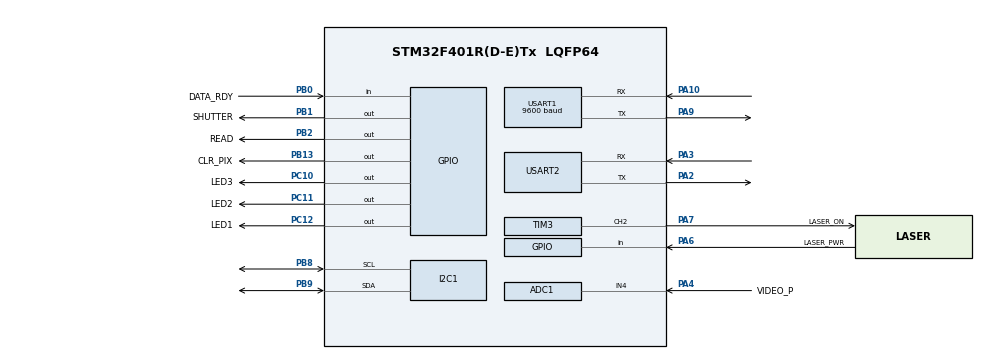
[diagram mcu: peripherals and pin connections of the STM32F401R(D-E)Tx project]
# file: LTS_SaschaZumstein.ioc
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ADC1.Channel-0\#ChannelRegularConversion=ADC_CHANNEL_4
ADC1.NbrOfConversionFlag=1
ADC1.Rank-0\#ChannelRegularConversion=1
ADC1.SamplingTime-0\#ChannelRegularConversion=ADC_SAMPLETIME_3CYCLES
ADC1.master=1
I2C1.I2C_Mode=I2C_Fast
Mcu.Family=STM32F4
Mcu.Name=STM32F401R(D-E)Tx
Mcu.Package=LQFP64
NVIC.PriorityGroup=NVIC_PRIORITYGROUP_4
PA10.Mode=Asynchronous
PA10.Signal=USART1_RX
PA13.Signal=SYS_JTMS-SWDIO
PA14.Signal=SYS_JTCK-SWCLK
PA2.Mode=Asynchronous
PA2.Signal=USART2_TX
PA3.Mode=Asynchronous
PA3.Signal=USART2_RX
PA4.GPIO_Label=VIDEO_P
PA4.Signal=SharedAnalog_PA4
PA6.GPIO_Label=LASER_PWR
PA6.Signal=GPIO_Input
PA7.GPIO_Label=LASER_ON
PA7.Signal=S_TIM3_CH2
PA9.Mode=Asynchronous
PA9.Signal=USART1_TX
PB0.GPIO_Label=DATA_RDY
PB0.Signal=GPIO_Input
PB1.GPIO_Label=SHUTTER
PB1.Signal=GPIO_Output
PB13.GPIO_Label=CLR_PIX
PB13.Signal=GPIO_Output
PB2.GPIO_Label=READ
PB2.Signal=GPIO_Output
PB8.Mode=I2C
PB8.Signal=I2C1_SCL
PB9.Mode=I2C
PB9.Signal=I2C1_SDA
PC10.GPIO_Label=LED3
PC10.Signal=GPIO_Output
PC11.GPIO_Label=LED2
PC11.Signal=GPIO_Output
PC12.GPIO_Label=LED1
PC12.Signal=GPIO_Output
ProjectManager.HeapSize=0x200
ProjectManager.StackSize=0x400
ProjectManager.TargetToolchain=STM32CubeIDE
RCC.AHBFreq_Value=16000000
RCC.APB1Freq_Value=16000000
RCC.APB2Freq_Value=16000000
RCC.CortexFreq_Value=16000000
RCC.HSE_VALUE=25000000
RCC.HSI_VALUE=16000000
RCC.LSE_VALUE=32768
RCC.SYSCLKFreq_VALUE=16000000
RCC.VCOOutputFreq_Value=192000000
SH.S_TIM3_CH2.0=TIM3_CH2,PWM Generation2 CH2
SH.SharedAnalog_PA4.0=GPIO_Analog
SH.SharedAnalog_PA4.1=ADC1_IN4,IN4
TIM3.Channel-PWM\ Generation2\ CH2=TIM_CHANNEL_2
TIM3.Period=49
TIM3.Prescaler=16-1
TIM3.Pulse-PWM\ Generation2\ CH2=15
TIM9.Prescaler=16-1
USART1.BaudRate=9600
USART1.VirtualMode=VM_ASYNC
USART2.VirtualMode=VM_ASYNC
VP_TIM3_VS_ClockSourceINT.Mode=Internal
VP_TIM9_VS_ClockSourceINT.Mode=Internal
board=custom

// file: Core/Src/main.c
/* USER CODE BEGIN Header */
/**
 ******************************************************************************
 * @file           : main.c
 * @brief          : Main program body
 ******************************************************************************
 * @attention
 *
 * Copyright (c) 2024 STMicroelectronics.
 * All rights reserved.
 *
 * This software is licensed under terms that can be found in the LICENSE file
 * in the root directory of this software component.
 * If no LICENSE file comes with this software, it is provided AS-IS.
 *
 ******************************************************************************
 */
/* USER CODE END Header */
#include "main.h"

/* USER CODE BEGIN Includes */
#include <stdio.h>
#include <stdbool.h>
#include "ssd1306.h"
#include "epc901.h"
#include "logic.h"

/* USER CODE END Includes */

/* USER CODE BEGIN PD */
#define NUM_OF_PIX 		1024
#define LASER_ON 		HAL_TIM_PWM_Start(&htim3, TIM_CHANNEL_2);
#define LASER_OFF		HAL_TIM_PWM_Stop(&htim3, TIM_CHANNEL_2);
#define LED_PWR_ON		HAL_GPIO_WritePin(LED1_GPIO_Port, LED1_Pin, GPIO_PIN_SET);
#define LED_PWR_OFF		HAL_GPIO_WritePin(LED1_GPIO_Port, LED1_Pin, GPIO_PIN_RESET);
#define LED_MEASURE_ON	HAL_GPIO_WritePin(LED2_GPIO_Port, LED2_Pin, GPIO_PIN_SET);
#define LED_MEASURE_OFF	HAL_GPIO_WritePin(LED2_GPIO_Port, LED2_Pin, GPIO_PIN_RESET);
#define LED_ERROR_ON	HAL_GPIO_WritePin(LED3_GPIO_Port, LED3_Pin, GPIO_PIN_SET);
#define LED_ERROR_OFF	HAL_GPIO_WritePin(LED3_GPIO_Port, LED3_Pin, GPIO_PIN_RESET);
#define CHECK_STATUS(status)       \
	do {                    	\
	if ((status) != HAL_OK) {	\
		Error_Handler();     	\
	}                        	\
} while (0)
/* USER CODE END PD */

ADC_HandleTypeDef hadc1;

I2C_HandleTypeDef hi2c1;

IWDG_HandleTypeDef hiwdg;

TIM_HandleTypeDef htim3;
TIM_HandleTypeDef htim9;

UART_HandleTypeDef huart1;
UART_HandleTypeDef huart2;

/* USER CODE BEGIN PV */
uint8_t rxBuffer[1];
volatile bool debugMode = false;
volatile bool fastMode = false;
/* USER CODE END PV */

void SystemClock_Config(void);
static void MX_GPIO_Init(void);
static void MX_ADC1_Init(void);
static void MX_I2C1_Init(void);
static void MX_USART1_UART_Init(void);
static void MX_USART2_UART_Init(void);
static void MX_TIM9_Init(void);
static void MX_TIM3_Init(void);
static void MX_IWDG_Init(void);

int main(void) {

	/* USER CODE BEGIN 1 */
	uint16_t distance = UINT16_MAX;
	char distStr[9];
	uint16_t shutterTime = 125;
	char shutterStr[22];
	uint16_t measureData[NUM_OF_PIX] = { 0 };
	uint16_t minVal = UINT16_MAX;
	uint16_t maxVal = 0;
	uint16_t maxIndex = 0;
	uint8_t txBuffer[1];
	/* USER CODE END 1 */

	/* MCU Configuration--------------------------------------------------------*/

	/* Reset of all peripherals, Initializes the Flash interface and the Systick. */
	HAL_Init();

	/* Configure the system clock */
	SystemClock_Config();

	/* USER CODE BEGIN SysInit */
	HAL_Delay(200); // delay to ensure that the display startup works correctly
	/* USER CODE END SysInit */

	/* Initialize all configured peripherals */
	MX_GPIO_Init();
	MX_ADC1_Init();
	MX_I2C1_Init();
	MX_USART1_UART_Init();
	MX_USART2_UART_Init();
	MX_TIM9_Init();
	MX_TIM3_Init();
	MX_IWDG_Init();
	/* USER CODE BEGIN 2 */
	// init display
	CHECK_STATUS(SSD1306_Init());
	SSD1306_PrintData("LTS Startup", "Please Wait");
	// init epc901
	CHECK_STATUS(HAL_TIM_Base_Start(&htim9));
	CHECK_STATUS(epc901_init());
	// init UART
	CHECK_STATUS(HAL_UART_Receive_IT(&huart2, rxBuffer, 1));
	logic_writeData("\r\n\n-- LTS Startup Please Wait --\r\n", 34, false);
	// delay to display startup screen
	for (int i = 0; i < 10; i++) {
		HAL_IWDG_Refresh(&hiwdg);
		HAL_Delay(200);
	}
	// startup sucessfully
	LASER_ON
	LED_PWR_ON
	LED_ERROR_OFF
	LED_MEASURE_OFF
	logic_writeData("\r\n\n-- LTS Startup successfully --\r\n", 35, false);
	SSD1306_Clear();
	/* USER CODE END 2 */

	/* Infinite loop */
	/* USER CODE BEGIN WHILE */
	while (1) {
		// get the data from the epc901
		CHECK_STATUS(epc901_getData(shutterTime, measureData, &minVal, &maxVal, &maxIndex));
		// regulate shutter time
		logic_adjustShutterTime(&shutterTime, minVal, maxVal);
		// calculate distance and make an average over the last values
		distance = logic_movingAverage(logic_calcDist(measureData, minVal, maxVal, maxIndex));

		if (distance == UINT16_MAX) { // measurement not successful
			if (!fastMode){ // don't write to the display in fast mode
				CHECK_STATUS(SSD1306_PrintData("Distance:", "---- mm"));
			}
			logic_writeData("Distance: ---- mm\r\n", 19, fastMode);
			LED_MEASURE_OFF
		}
		else { // measurement successful
			sprintf(distStr, "%4d mm", distance);
			if (!fastMode){ // don't write to the display in fast mode
				CHECK_STATUS(SSD1306_PrintData("Distance:", distStr));
			}
			logic_writeData("Distance: ", 10, fastMode);
			logic_writeData(distStr, 7, fastMode);
			logic_writeData("\r\n", 2, fastMode);
			LED_MEASURE_ON
		}

		// send shutter time and measured data via serial only if debug mode is activated
		if (debugMode) {
			sprintf(shutterStr, "Shutter Time: %4d\r\n", shutterTime);
			logic_writeData(shutterStr, 20, false);

			// transmit the data
			logic_writeData("START DATA\r\n", 12, true);
			for (int i = 0; i < NUM_OF_PIX; i++) {
				txBuffer[0] = measureData[i] >> 4;
				HAL_UART_Transmit(&huart2, txBuffer, 1, HAL_MAX_DELAY);
			}
			logic_writeData("\r\nEND DATA\r\n", 12, true);
		}
		/* USER CODE END WHILE */

		/* USER CODE BEGIN 3 */
		HAL_IWDG_Refresh(&hiwdg); // refresh watchdog
	}
	return 0;
	/* USER CODE END 3 */
}

void SystemClock_Config(void) {
	RCC_OscInitTypeDef RCC_OscInitStruct = { 0 };
	RCC_ClkInitTypeDef RCC_ClkInitStruct = { 0 };

	/** Configure the main internal regulator output voltage
	 */
	__HAL_RCC_PWR_CLK_ENABLE();
	__HAL_PWR_VOLTAGESCALING_CONFIG(PWR_REGULATOR_VOLTAGE_SCALE2);

	/** Initializes the RCC Oscillators according to the specified parameters
	 * in the RCC_OscInitTypeDef structure.
	 */
	RCC_OscInitStruct.OscillatorType = RCC_OSCILLATORTYPE_HSI
			| RCC_OSCILLATORTYPE_LSI;
	RCC_OscInitStruct.HSIState = RCC_HSI_ON;
	RCC_OscInitStruct.HSICalibrationValue = RCC_HSICALIBRATION_DEFAULT;
	RCC_OscInitStruct.LSIState = RCC_LSI_ON;
	RCC_OscInitStruct.PLL.PLLState = RCC_PLL_ON;
	RCC_OscInitStruct.PLL.PLLSource = RCC_PLLSOURCE_HSI;
	RCC_OscInitStruct.PLL.PLLM = 8;
	RCC_OscInitStruct.PLL.PLLN = 84;
	RCC_OscInitStruct.PLL.PLLP = RCC_PLLP_DIV2;
	RCC_OscInitStruct.PLL.PLLQ = 4;
	if (HAL_RCC_OscConfig(&RCC_OscInitStruct) != HAL_OK) {
		Error_Handler();
	}

	/** Initializes the CPU, AHB and APB buses clocks
	 */
	RCC_ClkInitStruct.ClockType = RCC_CLOCKTYPE_HCLK | RCC_CLOCKTYPE_SYSCLK
			| RCC_CLOCKTYPE_PCLK1 | RCC_CLOCKTYPE_PCLK2;
	RCC_ClkInitStruct.SYSCLKSource = RCC_SYSCLKSOURCE_PLLCLK;
	RCC_ClkInitStruct.AHBCLKDivider = RCC_SYSCLK_DIV1;
	RCC_ClkInitStruct.APB1CLKDivider = RCC_HCLK_DIV2;
	RCC_ClkInitStruct.APB2CLKDivider = RCC_HCLK_DIV1;

	if (HAL_RCC_ClockConfig(&RCC_ClkInitStruct, FLASH_LATENCY_2) != HAL_OK) {
		Error_Handler();
	}
}

static void MX_ADC1_Init(void) {

	ADC_ChannelConfTypeDef sConfig = { 0 };

	/** Configure the global features of the ADC (Clock, Resolution, Data Alignment and number of conversion)
	 */
	hadc1.Instance = ADC1;
	hadc1.Init.ClockPrescaler = ADC_CLOCK_SYNC_PCLK_DIV4;
	hadc1.Init.Resolution = ADC_RESOLUTION_12B;
	hadc1.Init.ScanConvMode = DISABLE;
	hadc1.Init.ContinuousConvMode = DISABLE;
	hadc1.Init.DiscontinuousConvMode = DISABLE;
	hadc1.Init.ExternalTrigConvEdge = ADC_EXTERNALTRIGCONVEDGE_NONE;
	hadc1.Init.ExternalTrigConv = ADC_SOFTWARE_START;
	hadc1.Init.DataAlign = ADC_DATAALIGN_RIGHT;
	hadc1.Init.NbrOfConversion = 1;
	hadc1.Init.DMAContinuousRequests = DISABLE;
	hadc1.Init.EOCSelection = ADC_EOC_SINGLE_CONV;
	if (HAL_ADC_Init(&hadc1) != HAL_OK) {
		Error_Handler();
	}

	/** Configure for the selected ADC regular channel its corresponding rank in the sequencer and its sample time.
	 */
	sConfig.Channel = ADC_CHANNEL_4;
	sConfig.Rank = 1;
	sConfig.SamplingTime = ADC_SAMPLETIME_3CYCLES;
	if (HAL_ADC_ConfigChannel(&hadc1, &sConfig) != HAL_OK) {
		Error_Handler();
	}

}

static void MX_I2C1_Init(void) {

	hi2c1.Instance = I2C1;
	hi2c1.Init.ClockSpeed = 400000;
	hi2c1.Init.DutyCycle = I2C_DUTYCYCLE_2;
	hi2c1.Init.OwnAddress1 = 0;
	hi2c1.Init.AddressingMode = I2C_ADDRESSINGMODE_7BIT;
	hi2c1.Init.DualAddressMode = I2C_DUALADDRESS_DISABLE;
	hi2c1.Init.OwnAddress2 = 0;
	hi2c1.Init.GeneralCallMode = I2C_GENERALCALL_DISABLE;
	hi2c1.Init.NoStretchMode = I2C_NOSTRETCH_DISABLE;
	if (HAL_I2C_Init(&hi2c1) != HAL_OK) {
		Error_Handler();
	}

}

static void MX_IWDG_Init(void) {

	hiwdg.Instance = IWDG;
	hiwdg.Init.Prescaler = IWDG_PRESCALER_8;
	hiwdg.Init.Reload = 4095;
	if (HAL_IWDG_Init(&hiwdg) != HAL_OK) {
		Error_Handler();
	}

}

static void MX_TIM3_Init(void) {

	TIM_ClockConfigTypeDef sClockSourceConfig = { 0 };
	TIM_MasterConfigTypeDef sMasterConfig = { 0 };
	TIM_OC_InitTypeDef sConfigOC = { 0 };

	htim3.Instance = TIM3;
	htim3.Init.Prescaler = 84 - 1;
	htim3.Init.CounterMode = TIM_COUNTERMODE_UP;
	htim3.Init.Period = 49;
	htim3.Init.ClockDivision = TIM_CLOCKDIVISION_DIV1;
	htim3.Init.AutoReloadPreload = TIM_AUTORELOAD_PRELOAD_DISABLE;
	if (HAL_TIM_Base_Init(&htim3) != HAL_OK) {
		Error_Handler();
	}
	sClockSourceConfig.ClockSource = TIM_CLOCKSOURCE_INTERNAL;
	if (HAL_TIM_ConfigClockSource(&htim3, &sClockSourceConfig) != HAL_OK) {
		Error_Handler();
	}
	if (HAL_TIM_PWM_Init(&htim3) != HAL_OK) {
		Error_Handler();
	}
	sMasterConfig.MasterOutputTrigger = TIM_TRGO_RESET;
	sMasterConfig.MasterSlaveMode = TIM_MASTERSLAVEMODE_DISABLE;
	if (HAL_TIMEx_MasterConfigSynchronization(&htim3, &sMasterConfig)
			!= HAL_OK) {
		Error_Handler();
	}
	sConfigOC.OCMode = TIM_OCMODE_PWM1;
	sConfigOC.Pulse = 15;
	sConfigOC.OCPolarity = TIM_OCPOLARITY_HIGH;
	sConfigOC.OCFastMode = TIM_OCFAST_DISABLE;
	if (HAL_TIM_PWM_ConfigChannel(&htim3, &sConfigOC, TIM_CHANNEL_2)
			!= HAL_OK) {
		Error_Handler();
	}
	HAL_TIM_MspPostInit(&htim3);

}

static void MX_TIM9_Init(void) {

	TIM_ClockConfigTypeDef sClockSourceConfig = { 0 };

	htim9.Instance = TIM9;
	htim9.Init.Prescaler = 84 - 1;
	htim9.Init.CounterMode = TIM_COUNTERMODE_UP;
	htim9.Init.Period = 65535;
	htim9.Init.ClockDivision = TIM_CLOCKDIVISION_DIV1;
	htim9.Init.AutoReloadPreload = TIM_AUTORELOAD_PRELOAD_DISABLE;
	if (HAL_TIM_Base_Init(&htim9) != HAL_OK) {
		Error_Handler();
	}
	sClockSourceConfig.ClockSource = TIM_CLOCKSOURCE_INTERNAL;
	if (HAL_TIM_ConfigClockSource(&htim9, &sClockSourceConfig) != HAL_OK) {
		Error_Handler();
	}

}

static void MX_USART1_UART_Init(void) {

	huart1.Instance = USART1;
	huart1.Init.BaudRate = 9600;
	huart1.Init.WordLength = UART_WORDLENGTH_8B;
	huart1.Init.StopBits = UART_STOPBITS_1;
	huart1.Init.Parity = UART_PARITY_NONE;
	huart1.Init.Mode = UART_MODE_TX_RX;
	huart1.Init.HwFlowCtl = UART_HWCONTROL_NONE;
	huart1.Init.OverSampling = UART_OVERSAMPLING_16;
	if (HAL_UART_Init(&huart1) != HAL_OK) {
		Error_Handler();
	}

}

static void MX_USART2_UART_Init(void) {

	huart2.Instance = USART2;
	huart2.Init.BaudRate = 115200;
	huart2.Init.WordLength = UART_WORDLENGTH_8B;
	huart2.Init.StopBits = UART_STOPBITS_1;
	huart2.Init.Parity = UART_PARITY_NONE;
	huart2.Init.Mode = UART_MODE_TX_RX;
	huart2.Init.HwFlowCtl = UART_HWCONTROL_NONE;
	huart2.Init.OverSampling = UART_OVERSAMPLING_16;
	if (HAL_UART_Init(&huart2) != HAL_OK) {
		Error_Handler();
	}

}

static void MX_GPIO_Init(void) {
	GPIO_InitTypeDef GPIO_InitStruct = { 0 };

	/* GPIO Ports Clock Enable */
	__HAL_RCC_GPIOA_CLK_ENABLE();
	__HAL_RCC_GPIOB_CLK_ENABLE();
	__HAL_RCC_GPIOC_CLK_ENABLE();

	/*Configure GPIO pin Output Level */
	HAL_GPIO_WritePin(GPIOB, SHUTTER_Pin | READ_Pin | CLR_PIX_Pin,
			GPIO_PIN_RESET);

	/*Configure GPIO pin Output Level */
	HAL_GPIO_WritePin(GPIOC, LED3_Pin | LED2_Pin | LED1_Pin, GPIO_PIN_RESET);

	/*Configure GPIO pin : LASER_PWR_Pin */
	GPIO_InitStruct.Pin = LASER_PWR_Pin;
	GPIO_InitStruct.Mode = GPIO_MODE_INPUT;
	GPIO_InitStruct.Pull = GPIO_NOPULL;
	HAL_GPIO_Init(LASER_PWR_GPIO_Port, &GPIO_InitStruct);

	/*Configure GPIO pin : DATA_RDY_Pin */
	GPIO_InitStruct.Pin = DATA_RDY_Pin;
	GPIO_InitStruct.Mode = GPIO_MODE_INPUT;
	GPIO_InitStruct.Pull = GPIO_NOPULL;
	HAL_GPIO_Init(DATA_RDY_GPIO_Port, &GPIO_InitStruct);

	/*Configure GPIO pins : SHUTTER_Pin READ_Pin CLR_PIX_Pin */
	GPIO_InitStruct.Pin = SHUTTER_Pin | READ_Pin | CLR_PIX_Pin;
	GPIO_InitStruct.Mode = GPIO_MODE_OUTPUT_PP;
	GPIO_InitStruct.Pull = GPIO_NOPULL;
	GPIO_InitStruct.Speed = GPIO_SPEED_FREQ_LOW;
	HAL_GPIO_Init(GPIOB, &GPIO_InitStruct);

	/*Configure GPIO pins : LED3_Pin LED2_Pin LED1_Pin */
	GPIO_InitStruct.Pin = LED3_Pin | LED2_Pin | LED1_Pin;
	GPIO_InitStruct.Mode = GPIO_MODE_OUTPUT_PP;
	GPIO_InitStruct.Pull = GPIO_NOPULL;
	GPIO_InitStruct.Speed = GPIO_SPEED_FREQ_LOW;
	HAL_GPIO_Init(GPIOC, &GPIO_InitStruct);

}

/* USER CODE BEGIN 4 */
/**
 * @brief Callback function of UART interrupt
 * @param UART handle type
 * @retval None
 */
void HAL_UART_RxCpltCallback(UART_HandleTypeDef *huart) {
	if (huart->Instance == USART2) {
		if (rxBuffer[0] == 'd') {
			debugMode = true;
			fastMode = false;
		}
		else if (rxBuffer[0] == 'f') {
			debugMode = false;
			fastMode = true;
			SSD1306_Clear();
		}
		else if (rxBuffer[0] == 'n') {
			debugMode = false;
			fastMode = false;
		}
		HAL_UART_Receive_IT(&huart2, rxBuffer, 1);
	}
}
/* USER CODE END 4 */

void Error_Handler(void) {
	/* USER CODE BEGIN Error_Handler_Debug */
	LASER_OFF
	LED_PWR_OFF
	LED_MEASURE_OFF
	LED_ERROR_ON
	SSD1306_PrintData("LTS Runtime", "Error      ");
	logic_writeData("\r\n\n-- LTS Runtime error --\r\n", 28, false);
	HAL_IWDG_Refresh(&hiwdg);
	while (1);
	/* USER CODE END Error_Handler_Debug */
}
